One B-rep face of a CAD part: STEP entity #1692.
In plain terms, the planar face has unit normal (1, 0, 0).
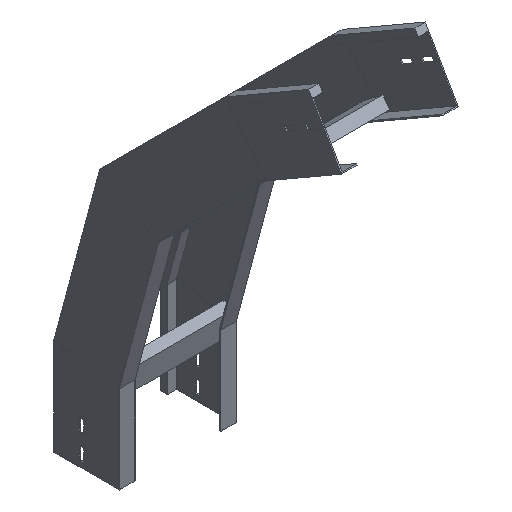
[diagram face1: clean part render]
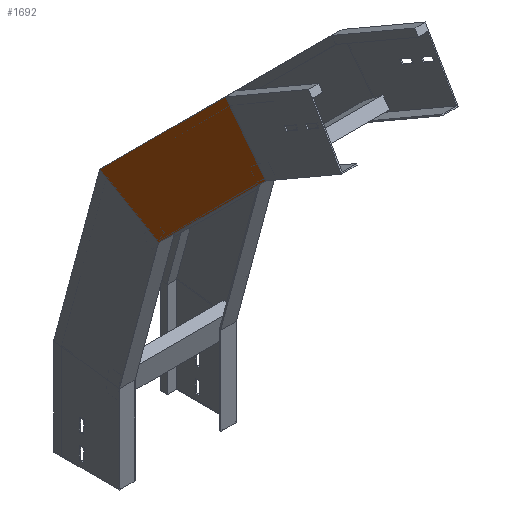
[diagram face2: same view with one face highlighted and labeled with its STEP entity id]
Its self-contained STEP definition (entity closure, numbers rounded to 3 decimals):
#39 = FACE_OUTER_BOUND ( 'NONE', #52, .T. ) ;
#52 = EDGE_LOOP ( 'NONE', ( #460, #318, #438, #977 ) ) ;
#110 = VECTOR ( 'NONE', #1658, 1000. ) ;
#133 = CARTESIAN_POINT ( 'NONE',  ( 0., -128.762, 364.536 ) ) ;
#138 = VERTEX_POINT ( 'NONE', #779 ) ;
#238 = CARTESIAN_POINT ( 'NONE',  ( 0., 4.243, 134.167 ) ) ;
#253 = EDGE_CURVE ( 'NONE', #1484, #138, #1524, .T. ) ;
#306 = CARTESIAN_POINT ( 'NONE',  ( 0., 4.243, 134.167 ) ) ;
#318 = ORIENTED_EDGE ( 'NONE', *, *, #1116, .T. ) ;
#383 = CARTESIAN_POINT ( 'NONE',  ( 0., 112.5, 164.811 ) ) ;
#399 = EDGE_CURVE ( 'NONE', #138, #1448, #1157, .T. ) ;
#438 = ORIENTED_EDGE ( 'NONE', *, *, #399, .F. ) ;
#460 = ORIENTED_EDGE ( 'NONE', *, *, #479, .T. ) ;
#479 = EDGE_CURVE ( 'NONE', #1484, #860, #568, .T. ) ;
#520 = VECTOR ( 'NONE', #1578, 1000. ) ;
#568 = LINE ( 'NONE', #1077, #1633 ) ;
#604 = PLANE ( 'NONE',  #765 ) ;
#734 = DIRECTION ( 'NONE',  ( 1., 0., 0. ) ) ;
#765 = AXIS2_PLACEMENT_3D ( 'NONE', #306, #734, #1620 ) ;
#779 = CARTESIAN_POINT ( 'NONE',  ( 0., 0., 150. ) ) ;
#804 = LINE ( 'NONE', #133, #520 ) ;
#860 = VERTEX_POINT ( 'NONE', #992 ) ;
#977 = ORIENTED_EDGE ( 'NONE', *, *, #253, .F. ) ;
#988 = VECTOR ( 'NONE', #1502, 1000. ) ;
#992 = CARTESIAN_POINT ( 'NONE',  ( 0., 33.831, 458.409 ) ) ;
#1077 = CARTESIAN_POINT ( 'NONE',  ( 0., 112.909, 163.284 ) ) ;
#1116 = EDGE_CURVE ( 'NONE', #860, #1448, #804, .T. ) ;
#1157 = LINE ( 'NONE', #238, #110 ) ;
#1319 = CARTESIAN_POINT ( 'NONE',  ( 0., -67.034, 400.175 ) ) ;
#1448 = VERTEX_POINT ( 'NONE', #1319 ) ;
#1484 = VERTEX_POINT ( 'NONE', #383 ) ;
#1502 = DIRECTION ( 'NONE',  ( 0., -0.991, -0.131 ) ) ;
#1524 = LINE ( 'NONE', #1640, #988 ) ;
#1578 = DIRECTION ( 'NONE',  ( 0., -0.866, -0.5 ) ) ;
#1597 = DIRECTION ( 'NONE',  ( 0., -0.259, 0.966 ) ) ;
#1620 = DIRECTION ( 'NONE',  ( 0., 0., -1. ) ) ;
#1633 = VECTOR ( 'NONE', #1597, 1000. ) ;
#1640 = CARTESIAN_POINT ( 'NONE',  ( 0., -19.411, 147.444 ) ) ;
#1658 = DIRECTION ( 'NONE',  ( 0., -0.259, 0.966 ) ) ;
#1692 = ADVANCED_FACE ( 'NONE', ( #39 ), #604, .T. ) ;
